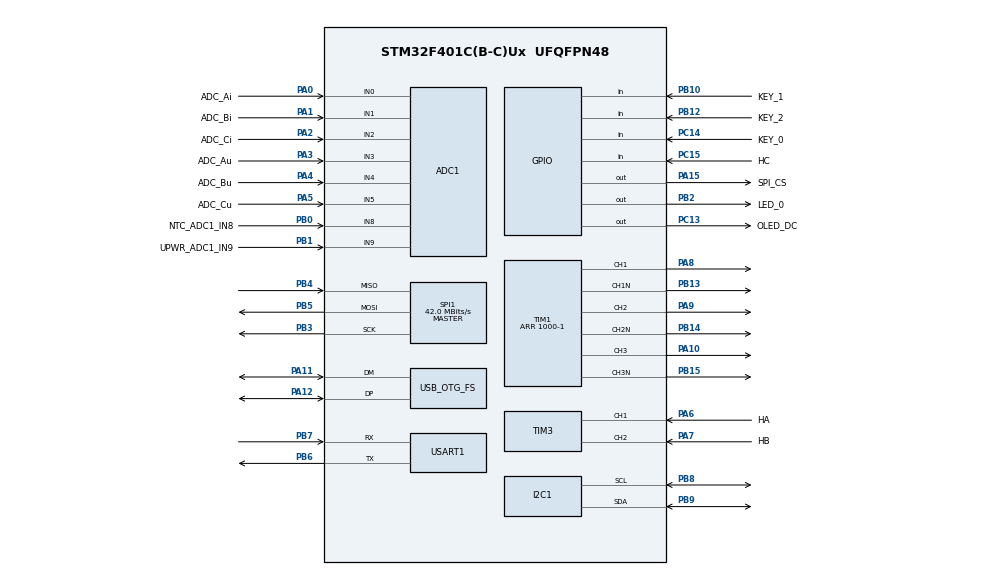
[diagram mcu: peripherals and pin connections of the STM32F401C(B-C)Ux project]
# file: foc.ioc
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ADC1.Channel-0\#ChannelRegularConversion=ADC_CHANNEL_0
ADC1.Channel-1\#ChannelRegularConversion=ADC_CHANNEL_1
ADC1.Channel-2\#ChannelRegularConversion=ADC_CHANNEL_2
ADC1.Channel-3\#ChannelRegularConversion=ADC_CHANNEL_3
ADC1.Channel-4\#ChannelRegularConversion=ADC_CHANNEL_4
ADC1.Channel-5\#ChannelRegularConversion=ADC_CHANNEL_5
ADC1.Channel-6\#ChannelRegularConversion=ADC_CHANNEL_8
ADC1.Channel-7\#ChannelRegularConversion=ADC_CHANNEL_9
ADC1.DMAContinuousRequests=ENABLE
ADC1.DiscontinuousConvMode=ENABLE
ADC1.EOCSelection=ADC_EOC_SEQ_CONV
ADC1.ExternalTrigConv=ADC_EXTERNALTRIGCONV_T2_TRGO
ADC1.NbrOfConversion=8
ADC1.NbrOfConversionFlag=1
ADC1.NbrOfDiscConversion=8
ADC1.Rank-0\#ChannelRegularConversion=1
ADC1.Rank-1\#ChannelRegularConversion=2
ADC1.Rank-2\#ChannelRegularConversion=3
ADC1.Rank-3\#ChannelRegularConversion=4
ADC1.Rank-4\#ChannelRegularConversion=5
ADC1.Rank-5\#ChannelRegularConversion=6
ADC1.Rank-6\#ChannelRegularConversion=7
ADC1.Rank-7\#ChannelRegularConversion=8
ADC1.SamplingTime-0\#ChannelRegularConversion=ADC_SAMPLETIME_3CYCLES
ADC1.SamplingTime-1\#ChannelRegularConversion=ADC_SAMPLETIME_3CYCLES
ADC1.SamplingTime-2\#ChannelRegularConversion=ADC_SAMPLETIME_3CYCLES
ADC1.SamplingTime-3\#ChannelRegularConversion=ADC_SAMPLETIME_3CYCLES
ADC1.SamplingTime-4\#ChannelRegularConversion=ADC_SAMPLETIME_3CYCLES
ADC1.SamplingTime-5\#ChannelRegularConversion=ADC_SAMPLETIME_3CYCLES
ADC1.SamplingTime-6\#ChannelRegularConversion=ADC_SAMPLETIME_3CYCLES
ADC1.SamplingTime-7\#ChannelRegularConversion=ADC_SAMPLETIME_3CYCLES
ADC1.master=1
Dma.ADC1.0.Direction=DMA_PERIPH_TO_MEMORY
Dma.ADC1.0.FIFOMode=DMA_FIFOMODE_DISABLE
Dma.ADC1.0.Instance=DMA2_Stream0
Dma.ADC1.0.MemDataAlignment=DMA_MDATAALIGN_HALFWORD
Dma.ADC1.0.MemInc=DMA_MINC_ENABLE
Dma.ADC1.0.Mode=DMA_CIRCULAR
Dma.ADC1.0.PeriphDataAlignment=DMA_PDATAALIGN_HALFWORD
Dma.ADC1.0.PeriphInc=DMA_PINC_DISABLE
Dma.ADC1.0.Priority=DMA_PRIORITY_VERY_HIGH
Dma.Request0=ADC1
Dma.Request1=TIM1_CH1
Dma.Request2=TIM1_CH2
Dma.Request3=TIM1_CH3
Dma.TIM1_CH1.1.Direction=DMA_MEMORY_TO_PERIPH
Dma.TIM1_CH1.1.FIFOMode=DMA_FIFOMODE_DISABLE
Dma.TIM1_CH1.1.Instance=DMA2_Stream1
Dma.TIM1_CH1.1.MemDataAlignment=DMA_MDATAALIGN_HALFWORD
Dma.TIM1_CH1.1.MemInc=DMA_MINC_ENABLE
Dma.TIM1_CH1.1.Mode=DMA_CIRCULAR
Dma.TIM1_CH1.1.PeriphDataAlignment=DMA_PDATAALIGN_HALFWORD
Dma.TIM1_CH1.1.PeriphInc=DMA_PINC_DISABLE
Dma.TIM1_CH1.1.Priority=DMA_PRIORITY_VERY_HIGH
Dma.TIM1_CH2.2.Direction=DMA_MEMORY_TO_PERIPH
Dma.TIM1_CH2.2.FIFOMode=DMA_FIFOMODE_DISABLE
Dma.TIM1_CH2.2.Instance=DMA2_Stream2
Dma.TIM1_CH2.2.MemDataAlignment=DMA_MDATAALIGN_HALFWORD
Dma.TIM1_CH2.2.MemInc=DMA_MINC_ENABLE
Dma.TIM1_CH2.2.Mode=DMA_CIRCULAR
Dma.TIM1_CH2.2.PeriphDataAlignment=DMA_PDATAALIGN_HALFWORD
Dma.TIM1_CH2.2.PeriphInc=DMA_PINC_DISABLE
Dma.TIM1_CH2.2.Priority=DMA_PRIORITY_VERY_HIGH
Dma.TIM1_CH3.3.Direction=DMA_MEMORY_TO_PERIPH
Dma.TIM1_CH3.3.FIFOMode=DMA_FIFOMODE_DISABLE
Dma.TIM1_CH3.3.Instance=DMA2_Stream6
Dma.TIM1_CH3.3.MemDataAlignment=DMA_MDATAALIGN_HALFWORD
Dma.TIM1_CH3.3.MemInc=DMA_MINC_ENABLE
Dma.TIM1_CH3.3.Mode=DMA_CIRCULAR
Dma.TIM1_CH3.3.PeriphDataAlignment=DMA_PDATAALIGN_HALFWORD
Dma.TIM1_CH3.3.PeriphInc=DMA_PINC_DISABLE
Dma.TIM1_CH3.3.Priority=DMA_PRIORITY_VERY_HIGH
Mcu.Family=STM32F4
Mcu.Name=STM32F401C(B-C)Ux
Mcu.Package=UFQFPN48
NVIC.ADC_IRQn=true\:0\:0\:false\:false\:true\:true\:true\:true
NVIC.DMA2_Stream0_IRQn=true\:0\:0\:false\:false\:true\:false\:true\:true
NVIC.DMA2_Stream1_IRQn=true\:0\:0\:false\:false\:true\:false\:true\:true
NVIC.DMA2_Stream2_IRQn=true\:0\:0\:false\:false\:true\:false\:true\:true
NVIC.DMA2_Stream6_IRQn=true\:0\:0\:false\:false\:true\:false\:true\:true
NVIC.PriorityGroup=NVIC_PRIORITYGROUP_4
NVIC.TIM1_TRG_COM_TIM11_IRQn=true\:0\:0\:false\:false\:true\:true\:true\:true
NVIC.TIM3_IRQn=true\:0\:0\:false\:false\:true\:true\:true\:true
PA0-WKUP.GPIO_Label=ADC_Ai
PA0-WKUP.Signal=ADCx_IN0
PA1.GPIO_Label=ADC_Bi
PA1.Signal=ADCx_IN1
PA10.Signal=S_TIM1_CH3
PA11.Mode=Device_Only
PA11.Signal=USB_OTG_FS_DM
PA12.Mode=Device_Only
PA12.Signal=USB_OTG_FS_DP
PA13.Mode=Serial_Wire
PA13.Signal=SYS_JTMS-SWDIO
PA14.Mode=Serial_Wire
PA14.Signal=SYS_JTCK-SWCLK
PA15.GPIO_Label=SPI_CS
PA15.GPIO_Speed=GPIO_SPEED_FREQ_VERY_HIGH
PA15.PinState=GPIO_PIN_SET
PA15.Signal=GPIO_Output
PA2.GPIO_Label=ADC_Ci
PA2.Signal=ADCx_IN2
PA3.GPIO_Label=ADC_Au
PA3.Signal=ADCx_IN3
PA4.GPIO_Label=ADC_Bu
PA4.Signal=ADCx_IN4
PA5.GPIO_Label=ADC_Cu
PA5.Signal=ADCx_IN5
PA6.GPIO_Label=HA
PA6.Signal=S_TIM3_CH1
PA7.GPIO_Label=HB
PA7.Signal=S_TIM3_CH2
PA8.Signal=S_TIM1_CH1
PA9.Signal=S_TIM1_CH2
PB0.GPIO_Label=NTC_ADC1_IN8
PB0.Signal=ADCx_IN8
PB1.GPIO_Label=UPWR_ADC1_IN9
PB1.Signal=ADCx_IN9
PB10.GPIO_Label=KEY_1
PB10.GPIO_Mode=GPIO_MODE_INPUT
PB10.GPIO_PuPd=GPIO_PULLUP
PB10.Signal=GPIO_Input
PB12.GPIO_Label=KEY_2
PB12.GPIO_Mode=GPIO_MODE_INPUT
PB12.GPIO_PuPd=GPIO_PULLUP
PB12.Signal=GPIO_Input
PB13.Mode=PWM Generation1 CH1 CH1N
PB13.Signal=TIM1_CH1N
PB14.Mode=PWM Generation2 CH2 CH2N
PB14.Signal=TIM1_CH2N
PB15.Mode=PWM Generation3 CH3 CH3N
PB15.Signal=TIM1_CH3N
PB2.GPIO_Label=LED_0
PB2.GPIO_Speed=GPIO_SPEED_FREQ_VERY_HIGH
PB2.PinState=GPIO_PIN_SET
PB2.Signal=GPIO_Output
PB3.Mode=Full_Duplex_Master
PB3.Signal=SPI1_SCK
PB4.Mode=Full_Duplex_Master
PB4.Signal=SPI1_MISO
PB5.Mode=Full_Duplex_Master
PB5.Signal=SPI1_MOSI
PB6.Mode=Asynchronous
PB6.Signal=USART1_TX
PB7.Mode=Asynchronous
PB7.Signal=USART1_RX
PB8.Mode=I2C
PB8.Signal=I2C1_SCL
PB9.Mode=I2C
PB9.Signal=I2C1_SDA
PC13-ANTI_TAMP.GPIO_Label=OLED_DC
PC13-ANTI_TAMP.GPIO_PuPd=GPIO_NOPULL
PC13-ANTI_TAMP.GPIO_Speed=GPIO_SPEED_FREQ_LOW
PC13-ANTI_TAMP.PinState=GPIO_PIN_SET
PC13-ANTI_TAMP.Signal=GPIO_Output
PC14-OSC32_IN.GPIO_Label=KEY_0
PC14-OSC32_IN.GPIO_PuPd=GPIO_PULLUP
PC14-OSC32_IN.Signal=GPIO_Input
PC15-OSC32_OUT.GPIO_Label=HC
PC15-OSC32_OUT.Signal=GPIO_Input
PH0\ -\ OSC_IN.Mode=HSE-External-Oscillator
PH0\ -\ OSC_IN.Signal=RCC_OSC_IN
PH1\ -\ OSC_OUT.Mode=HSE-External-Oscillator
PH1\ -\ OSC_OUT.Signal=RCC_OSC_OUT
ProjectManager.HeapSize=0x800
ProjectManager.StackSize=0x1000
ProjectManager.TargetToolchain=STM32CubeIDE
RCC.48MHZClocksFreq_Value=48000000
RCC.AHBFreq_Value=84000000
RCC.APB1CLKDivider=RCC_HCLK_DIV2
RCC.APB1Freq_Value=42000000
RCC.APB1TimFreq_Value=84000000
RCC.APB2Freq_Value=84000000
RCC.APB2TimFreq_Value=84000000
RCC.CortexFreq_Value=84000000
RCC.HCLKFreq_Value=84000000
RCC.HSE_VALUE=8000000
RCC.HSI_VALUE=16000000
RCC.LSE_VALUE=32768
RCC.PLLM=4
RCC.PLLN=168
RCC.PLLP=RCC_PLLP_DIV4
RCC.PLLQ=7
RCC.SYSCLKFreq_VALUE=84000000
RCC.SYSCLKSource=RCC_SYSCLKSOURCE_PLLCLK
RCC.VCOOutputFreq_Value=336000000
SH.ADCx_IN0.0=ADC1_IN0,IN0
SH.ADCx_IN1.0=ADC1_IN1,IN1
SH.ADCx_IN2.0=ADC1_IN2,IN2
SH.ADCx_IN3.0=ADC1_IN3,IN3
SH.ADCx_IN4.0=ADC1_IN4,IN4
SH.ADCx_IN5.0=ADC1_IN5,IN5
SH.ADCx_IN8.0=ADC1_IN8,IN8
SH.ADCx_IN9.0=ADC1_IN9,IN9
SH.S_TIM1_CH1.0=TIM1_CH1,PWM Generation1 CH1 CH1N
SH.S_TIM1_CH2.0=TIM1_CH2,PWM Generation2 CH2 CH2N
SH.S_TIM1_CH3.0=TIM1_CH3,PWM Generation3 CH3 CH3N
SH.S_TIM3_CH1.0=TIM3_CH1,Encoder_Interface
SH.S_TIM3_CH2.0=TIM3_CH2,Encoder_Interface
SPI1.CalculateBaudRate=42.0 MBits/s
SPI1.Direction=SPI_DIRECTION_2LINES
SPI1.Mode=SPI_MODE_MASTER
SPI1.VirtualType=VM_MASTER
TIM1.AutoReloadPreload=TIM_AUTORELOAD_PRELOAD_ENABLE
TIM1.Channel-PWM\ Generation1\ CH1\ CH1N=TIM_CHANNEL_1
TIM1.Channel-PWM\ Generation2\ CH2\ CH2N=TIM_CHANNEL_2
TIM1.Channel-PWM\ Generation3\ CH3\ CH3N=TIM_CHANNEL_3
TIM1.CounterMode=TIM_COUNTERMODE_CENTERALIGNED1
TIM1.Period=1000-1
TIM11.AutoReloadPreload=TIM_AUTORELOAD_PRELOAD_ENABLE
TIM11.Period=999
TIM11.Prescaler=27
TIM2.AutoReloadPreload=TIM_AUTORELOAD_PRELOAD_ENABLE
TIM2.Period=99
TIM2.Prescaler=83
TIM2.TIM_MasterOutputTrigger=TIM_TRGO_UPDATE
TIM3.AutoReloadPreload=TIM_AUTORELOAD_PRELOAD_ENABLE
USART1.VirtualMode=VM_ASYNC
USB_OTG_FS.VirtualMode=Device_Only
VP_TIM11_VS_ClockSourceINT.Mode=Enable_Timer
VP_TIM1_VS_ClockSourceINT.Mode=Internal
VP_TIM2_VS_ClockSourceINT.Mode=Internal
board=custom

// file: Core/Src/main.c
/* USER CODE BEGIN Header */
/**
  ******************************************************************************
  * @file           : main.c
  * @brief          : Main program body
  ******************************************************************************
  * @attention
  *
  * Copyright (c) 2023 STMicroelectronics.
  * All rights reserved.
  *
  * This software is licensed under terms that can be found in the LICENSE file
  * in the root directory of this software component.
  * If no LICENSE file comes with this software, it is provided AS-IS.
  *
  ******************************************************************************
  */
/* USER CODE END Header */
#include "main.h"
#include "adc.h"
#include "dma.h"
#include "i2c.h"
#include "spi.h"
#include "tim.h"
#include "usart.h"
#include "usb_otg.h"
#include "gpio.h"

/* USER CODE BEGIN Includes */
#include "stdarg.h"
#include "stdio.h"

#include "foc.h"
/* USER CODE END Includes */

void SystemClock_Config(void);

/* USER CODE BEGIN 0 */
int UART_printf(UART_HandleTypeDef *huart, const char *fmt, ...) {
    va_list ap;
    va_start(ap, fmt);
    int length;
    char buffer[128];
    length = vsnprintf(buffer, 128, fmt, ap);
    HAL_UART_Transmit(huart,buffer,length,HAL_MAX_DELAY);//HAL_MAX_DELAY
//    CDC_Transmit_FS((uint8_t*)buffer,length);
    va_end(ap);
    return length;
}
/* USER CODE END 0 */

int main(void)
{

  /* MCU Configuration--------------------------------------------------------*/

  /* Reset of all peripherals, Initializes the Flash interface and the Systick. */
  HAL_Init();

  /* Configure the system clock */
  SystemClock_Config();

  /* Initialize all configured peripherals */
  MX_GPIO_Init();
  MX_DMA_Init();
  MX_I2C1_Init();
  MX_ADC1_Init();
  MX_SPI1_Init();
  MX_TIM1_Init();
  MX_TIM3_Init();
  MX_USART1_UART_Init();
  MX_USB_OTG_FS_PCD_Init();
  MX_TIM2_Init();
  MX_TIM11_Init();

  /* Infinite loop */
  /* USER CODE BEGIN WHILE */
    //encoder_init
    if(as5600_init()==AS5600_OK)
        UART_printf(&huart1,"AS_OK\n\n");
    else
    {
        while(as5600_init()!=AS5600_OK)
        {
            UART_printf(&huart1,"err\n\n");
            HAL_IIC_BusyErrorHandler();
        }
    }
    FOC foc={0};
  while (1)
  {
      HAL_GPIO_WritePin(GPIOC,GPIO_PIN_13,0);
      as5600_read_angle(&foc);
      UART_printf(&huart1,"angle:%f\r\n",foc.angle);
      HAL_Delay(1000);

    /* USER CODE END WHILE */

  }
}

void SystemClock_Config(void)
{
  RCC_OscInitTypeDef RCC_OscInitStruct = {0};
  RCC_ClkInitTypeDef RCC_ClkInitStruct = {0};

  /** Configure the main internal regulator output voltage
  */
  __HAL_RCC_PWR_CLK_ENABLE();
  __HAL_PWR_VOLTAGESCALING_CONFIG(PWR_REGULATOR_VOLTAGE_SCALE2);

  /** Initializes the RCC Oscillators according to the specified parameters
  * in the RCC_OscInitTypeDef structure.
  */
  RCC_OscInitStruct.OscillatorType = RCC_OSCILLATORTYPE_HSE;
  RCC_OscInitStruct.HSEState = RCC_HSE_ON;
  RCC_OscInitStruct.PLL.PLLState = RCC_PLL_ON;
  RCC_OscInitStruct.PLL.PLLSource = RCC_PLLSOURCE_HSE;
  RCC_OscInitStruct.PLL.PLLM = 25;
  RCC_OscInitStruct.PLL.PLLN = 336;
  RCC_OscInitStruct.PLL.PLLP = RCC_PLLP_DIV4;
  RCC_OscInitStruct.PLL.PLLQ = 7;
  if (HAL_RCC_OscConfig(&RCC_OscInitStruct) != HAL_OK)
  {
    Error_Handler();
  }

  /** Initializes the CPU, AHB and APB buses clocks
  */
  RCC_ClkInitStruct.ClockType = RCC_CLOCKTYPE_HCLK|RCC_CLOCKTYPE_SYSCLK
                              |RCC_CLOCKTYPE_PCLK1|RCC_CLOCKTYPE_PCLK2;
  RCC_ClkInitStruct.SYSCLKSource = RCC_SYSCLKSOURCE_PLLCLK;
  RCC_ClkInitStruct.AHBCLKDivider = RCC_SYSCLK_DIV1;
  RCC_ClkInitStruct.APB1CLKDivider = RCC_HCLK_DIV2;
  RCC_ClkInitStruct.APB2CLKDivider = RCC_HCLK_DIV1;

  if (HAL_RCC_ClockConfig(&RCC_ClkInitStruct, FLASH_LATENCY_2) != HAL_OK)
  {
    Error_Handler();
  }
}

void Error_Handler(void)
{
  __disable_irq();
  while (1)
  {
  }
}
